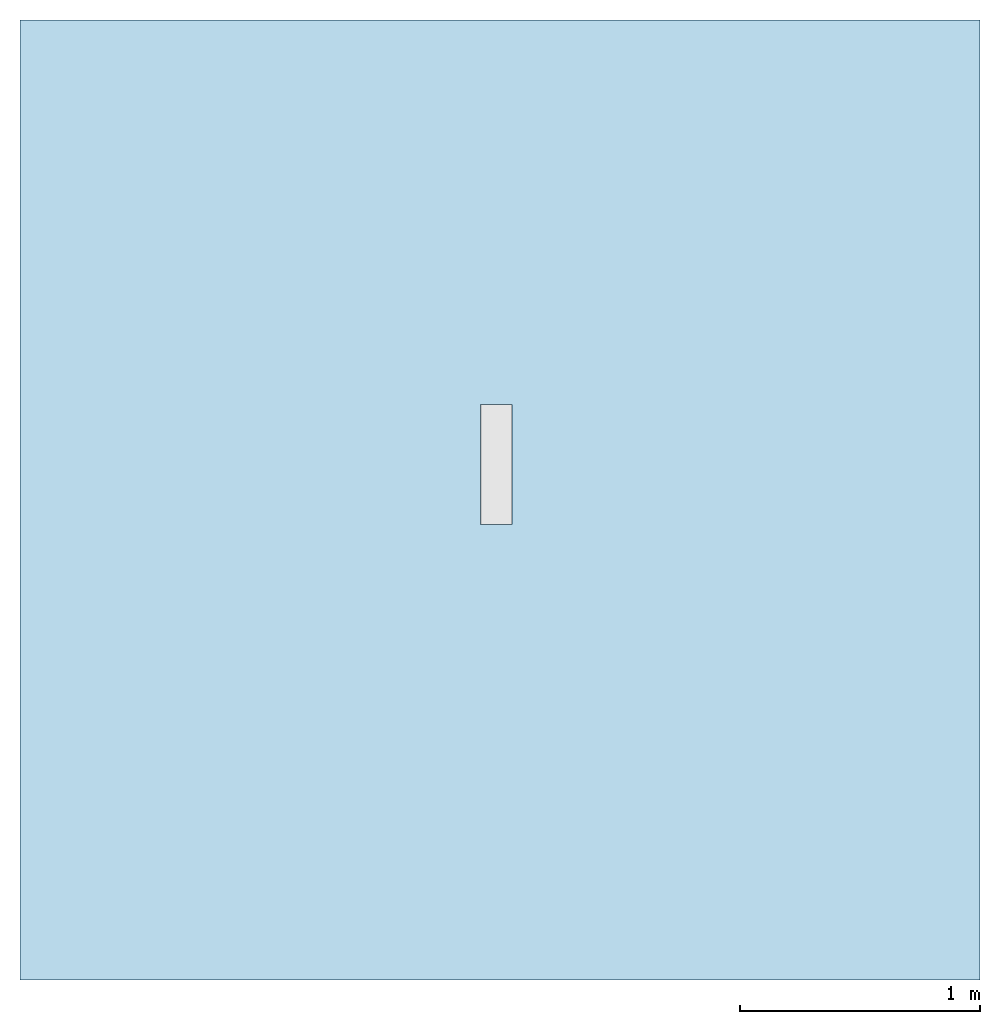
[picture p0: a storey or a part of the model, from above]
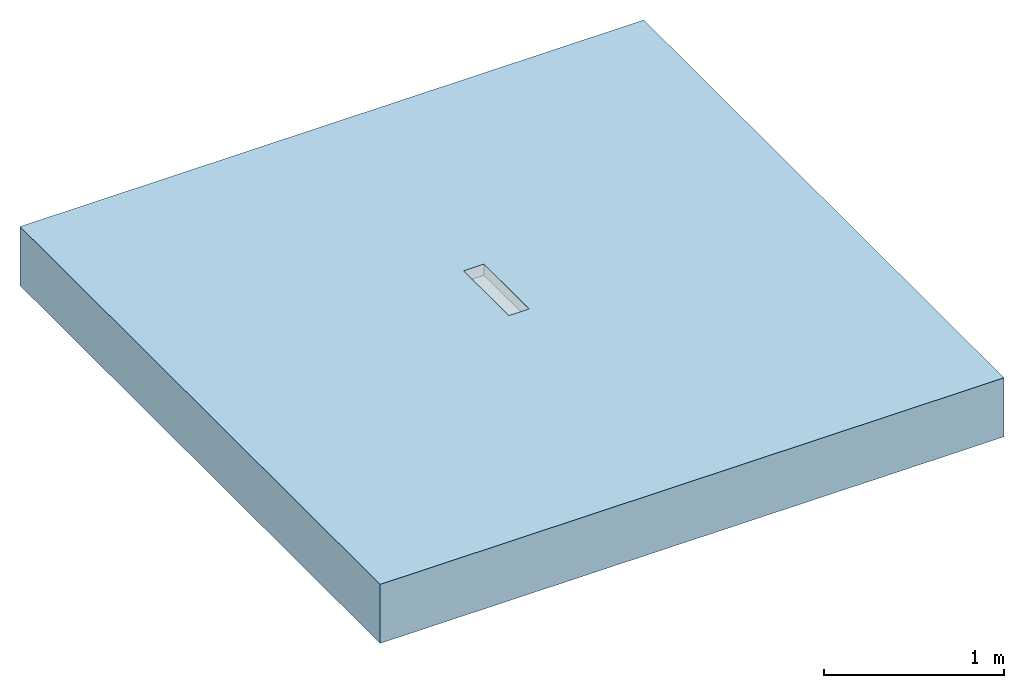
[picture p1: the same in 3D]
Properties of the parts of a building model (IFC2X3)

# File
Description: ViewDefinition [CoordinationView]
File name: Project Number
Time: 2014-06-06T15:02:45
Written by: The EXPRESS Data Manager Version 5.01.0100.02.64mod : 6 Jun 2012
Made in: 20130308_1515(x64) - Exporter 2014.0.2013.0308 - Default UI
Comment: STEP Physical File produced by: The EXPRESS Data Manager Version 5.01.0100.02.64mod : 6 Jun 2012 * Module: EDMstepFileFactory/EDMstandAlone * Creation date: Fri Jun 06 15:02:45 2014 * Host: IN-BLR-PC-0010 * Database: C:\Users\palleri\AppData\Local\Temp\{771020D0-8E6E-491D-A06A-EDE1DE3FFD47}\ifc * Database version: 5507 * Database creation date: Fri Jun 06 15:02:44 2014 * Schema: IFC2X3 * Model: DataRepository.ifc * Model creation date: Fri Jun 06 15:02:44 2014 * Header model: DataRepository.ifc_HeaderModel * Header model creation date: Fri Jun 06 15:02:44 2014 * EDMuser: sdai-user * EDMgroup: sdai-group * License ID and type: 5605 : Permanent license. Expiry date: * EDMstepFileFactory options: 020000

# IfcProject, Project Number
LongName: Project Name; Phase: Project Status

# IfcSite, Default
RefLatitude: 42, 21, 30, 344238; RefLongitude: -71, -3, -35, -194702; RefElevation: 0 mm

# IfcBuilding
Pset_BuildingCommon - NumberOfStoreys: 1
Other - Project Number: Project Number; Project Name: Project Name; Project Issue Date: Issue Date; Project Address: ## Street City, State Zip; Project Status: Project Status; Client Name: Owner

# IfcBuildingStorey, Level 1
LongName: Level 1; Elevation: 0 mm
Graphics - Symbol: M_Level Head - Circle: M_Level Head - Circle; Symbol at End 2 Default: yes; Line Weight: 1; Color: 0; Symbol at End 1 Default: no; Line Pattern: Center
Constraints - Elevation Base: Project Base Point; Elevation: 0 mm
Dimensions - Computation Height: 0 mm
Identity Data - Structural: no; Name: Level 1; Building Story: yes

# IfcFlowTerminal: 36987 - Fixed Height Channel - Shallow Section - 500mm LG - Invert Depth 75mm, ACO Freedeck Fixed Height Channel Intermediate Section Stainless Steel:36987 - Fixed Height Channel - Shallow Section - 500mm LG - Invert Depth 75mm:322678
In: Level 1
Material: Stainless Steel Grade 304
Construction - 36955 - Grating - Plain Mesh - Stainless Steel 304 - 1000mm long: yes; 00272 - Grating - Slotted Grating - Stainless Steel 304 - 1000mm long: no; End Plate Invert 2: no; 00273 - Grating - Slotted Grating - Stainless Steel 304 - 500mm long: no; 36954 - Grating - Plain Mesh - Stainless Steel 304 - 500mm long: no; End Plate Invert 1: no
Constraints - Moves With Nearby Elements: no; Level: Level: Level 1
Phasing - Phase Created: New Construction
Identity Data - Mark: 29; Watermarked With: BIM Manager Premium Suite; E-mail Sales: abdcommercial@aco.co.uk; Watermark2: This file is water marked and users are prohibited to reproduce, adapt, distribute this information; Manufacturer: ACO Building Drainage; Watermarked By: www.acobd.com; Address: ACO Business Centre, Caxton Road, Bedford, MK41 0LF; Watermark1: This file is the property of ACO Technologies PLC; Telephone: +44 (0)1462 816666; E-mail Technical: abdtechnical@aco.co.uk; Fax: +44 (0)1462 851490; Website: www.acobd.com
Pset_ManufacturerTypeInformation - Manufacturer: ACO Building Drainage
Model Properties - Grating Product Code 36955: Load Class A15 - Mesh Grating - 14mm x 30mm Mesh - Stainless Steel 304 - 1000mm long - 3.0kg; Grating Product Code 36954: Load Class A15 - Mesh Grating - 14mm x 30mm Mesh - Stainless Steel 304 - 500mm long - 1.6kg; End Plate Product Code 36988: End Plate - Stainless Steel for Invert Depth - 75mm - 0.07Kg; Grating Product Code 00272: Load Class A15 - Slotted Grating - 10 x 80mm Slot - Stainless Steel 304 - 1000mm long - 2.2kg; Grating Product Code 00273: Load Class A15 - Slotted Grating - 10 x 80mm Slot - Stainless Steel 304 - 500mm long - 1.0kg
Other - Side Void: 2; Nos: 16
Dimensions - Grating End Length: 500 mm; Height: 75 mm; Channel End Length: -500 mm
General - Channel Colour: Mid Grey; Product Type: Linear Deck Drainage System; Weight (Kg): 1.5kg; Product Standard: BS EN 1433:2002, CE marked; Price: POA - contact ACO; Channel Recyclable: Fully recyclable; Product Range: ACO Freedeck; Installation Guidelines: X:\Electronic Literature\ABD Electronic Literature\Roof and Balcony Drainage\ACO Freedeck Brochure.pdf; Channel Recycled Material Content: 60-70%; Dimensions (LxWxH): 500 x 130 x 75; NBS Specification: NBS Section R10 Gravity Rainwater Drainage Systems, Subsection 365; Product Code: 36987; Load Class: A15; Channel Material: Stainless Steel Grade 304; Product Description: ACO FreeDeck Fixed Height Channel - Intermediate Section; Maintenance Guidelines: X:\Electronic Literature\ABD Electronic Literature\Roof and Balcony Drainage\ACO Freedeck Brochure.pdf
Materials and Finishes - Material: Stainless Steel Grade 304

# IfcSlab: Floor:Generic Floor - 400mm, Floor:Generic Floor - 400mm:193825
In: Level 1
PredefinedType: FLOOR; Material: Concrete, Broom Finish 400 mm
Phasing - Phase Created: New Construction
Dimensions - Volume: 6.39513 m3; Thickness: 400 mm; Area: 16 m2; Perimeter: 16000 mm
Structural - Enable Analytical Model: no; Structural: no
Constraints - Room Bounding: yes; Level: Level: Level 1; Height Offset From Level: 0 mm; Related to Mass: no
Pset_SlabCommon - Reference: Generic Floor - 400mm; IsExternal: no; LoadBearing: yes; ThermalTransmittance: 2.615 kg/K/s3; PitchAngle: 0 deg
Construction - Default Thickness: 400 mm; Function: Interior
Graphics - Coarse Scale Fill Color: 0
Analytical Properties - Roughness: 1; Absorptance: 0.1; Thermal mass: 604440; Thermal Resistance (R): 0.382409; Heat Transfer Coefficient (U): 2.615
Materials and Finishes - Structural Material: Concrete, Broom Finish
